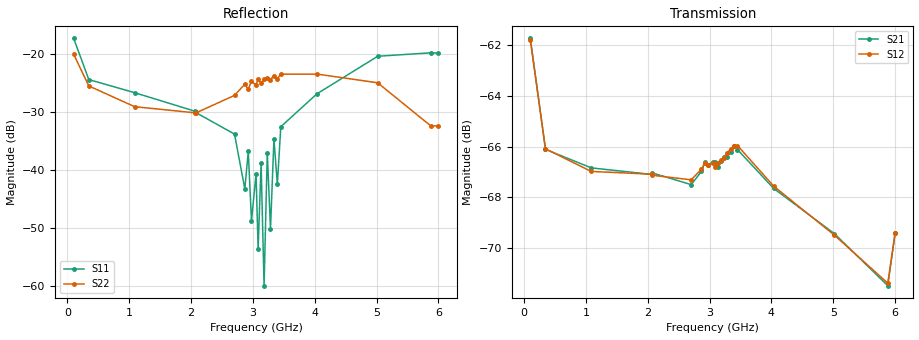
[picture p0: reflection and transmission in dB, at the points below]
!Agilent Technologies,E5071C,MY46316741,A.11.02
!Date: Thu Dec 16 09:41:00 2021
!Data & Calibration Information:
!Freq	S11:SOLT4(ON)	S21:SOLT4(ON)	S12:SOLT4(ON)	S22:SOLT4(ON)
!PortZ  Port1:50+j0  Port2:50+j0
!Above PortZ is port z conversion or system Z0 setting when saving the data.
!When reading, reference impedance value at option line is always used.
# Hz S dB R 50
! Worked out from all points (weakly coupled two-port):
!   1593 points, 100 MHz to 6 GHz, reference 50 ohm
!   highest |S21| = -61.74 dB at 100 MHz (marker M1); lowest = -71.5 dB at 5.881 GHz (marker M2)
!   lowest |S11| = -59.9 dB at 3.18 GHz (marker M3), VSWR 1.00, Z = 49.9 - j0.0805 ohm
!   |S11| at or under -10 dB: start of sweep to end of sweep
!   |S22| runs from -32.6 to -20.1 dB; largest |S21 - S12| = 2.1e-05
!   S11 on the Smith chart (normalised r, x): 100 MHz: 0.92, -0.25; 2.072 GHz: 1.02, +0.06; 6 GHz: 1.09, -0.19
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1e8  -17.33 -100.5  -61.74 -99.9  -61.82 -99.6  -20.08 -115.6
3.44598e8  -24.42 -156.7  -66.11 -75.3  -66.09 -75.0  -25.52 -168.4
1.085804e9  -26.68 136.0  -66.84 -159.2  -66.98 -159.6  -29.09 145.4
2.067902e9  -29.89 69.5  -67.10 74.7  -67.09 75.3  -30.15 152.4
2.071608e9  -30.07 68.6  -67.04 74.1  -67.13 75.7  -30.19 152.9
2.701633e9  -33.81 1.6  -67.50 -5.9  -67.31 -6.6  -27.14 133.8
2.868405e9  -43.27 -21.2  -66.98 -27.8  -66.89 -27.9  -25.22 129.6
2.923995e9  -36.75 -32.8  -66.60 -37.6  -66.64 -37.8  -26.08 125.5
2.975879e9  -48.74 -37.5  -66.72 -44.4  -66.73 -44.8  -24.70 123.5
3.05e9  -40.63 -41.6  -66.60 -55.4  -66.65 -54.8  -25.36 117.2
3.083354e9  -53.58 -118.5  -66.60 -60.1  -66.79 -60.0  -24.30 117.3
3.131533e9  -38.85 -102.6  -66.81 -64.8  -66.65 -66.2  -25.04 119.7
3.179711e9  -59.90 -127.2  -66.58 -71.0  -66.52 -72.1  -24.40 109.6
3.231595e9  -37.02 -148.2  -66.43 -80.1  -66.45 -80.0  -24.20 114.9
3.28348e9  -50.13 -151.0  -66.40 -86.0  -66.24 -85.5  -24.42 104.6
3.33907e9  -34.66 -177.6  -66.22 -94.5  -66.10 -94.6  -23.73 108.9
3.394661e9  -42.47 176.3  -65.97 -103.6  -65.97 -102.9  -24.27 99.1
3.450251e9  -32.54 165.3  -66.12 -112.1  -65.96 -113.7  -23.48 102.6
4.035804e9  -26.87 114.0  -67.65 169.4  -67.56 170.4  -23.48 69.3
5.017902e9  -20.41 24.2  -69.43 45.2  -69.49 46.6  -24.98 13.2
5.881407e9  -19.81 -49.6  -71.48 -72.0  -71.38 -71.3  -32.44 14.1
6e9  -19.87 -59.0  -69.41 -70.2  -69.42 -69.5  -32.35 21.3
